VERSION 5.8 ;
BUSBITCHARS "[]" ;
DIVIDERCHAR "/" ;

SITE  CoreSite4
    CLASS       CORE ;
    SYMMETRY    Y ;
    SIZE        0.48 BY 15.12 ;
END  CoreSite4

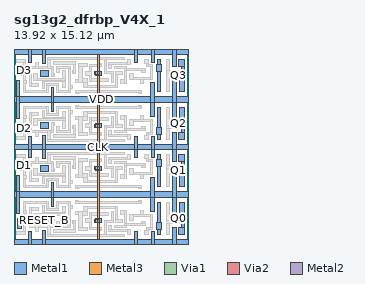
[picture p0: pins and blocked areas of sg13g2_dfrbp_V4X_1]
MACRO sg13g2_dfrbp_V4X_1
  CLASS CORE ;
  ORIGIN 0 0 ;
  FOREIGN sg13g2_dfrbp_V4X_1 0 0 ;
  SIZE 13.920 BY 15.120 ;
  SYMMETRY X Y ;
  SITE CoreSite4 ;
  PIN D0
    DIRECTION INPUT ;
    USE SIGNAL ;
    ANTENNAMODEL OXIDE1 ;
    ANTENNAGATEAREA 0.1092 LAYER Metal1 ;
    PORT
      LAYER Metal1 ;
        RECT 0.255 1.070 0.600 1.890 ;
    END
  END D0
  PIN Q0
    DIRECTION OUTPUT ;
    USE SIGNAL ;
    ANTENNADIFFAREA 0.6324 LAYER Metal1 ;
    PORT
      LAYER Metal1 ;
        RECT 13.125 0.590 13.560 1.190 ;
        RECT 13.350 0.590 13.560 3.155 ;
        RECT 13.145 2.095 13.560 3.155 ;
    END
  END Q0
  PIN Q_N0
    DIRECTION OUTPUT ;
    USE SIGNAL ;
    ANTENNADIFFAREA 0.7161 LAYER Metal1 ;
    PORT
      LAYER Metal1 ;
        RECT 11.340 0.990 11.725 1.520 ;
        RECT 11.400 0.590 11.660 3.155 ;
    END
  END Q_N0
  PIN D1
    DIRECTION INPUT ;
    USE SIGNAL ;
    ANTENNAMODEL OXIDE1 ;
    ANTENNAGATEAREA 0.1092 LAYER Metal1 ;
    PORT
      LAYER Metal1 ;
        RECT 0.255 5.670 0.600 6.490 ;
    END
  END D1
  PIN Q1
    DIRECTION OUTPUT ;
    USE SIGNAL ;
    ANTENNADIFFAREA 0.6324 LAYER Metal1 ;
    PORT
      LAYER Metal1 ;
        RECT 13.145 4.405 13.560 5.465 ;
        RECT 13.350 4.405 13.560 6.970 ;
        RECT 13.125 6.370 13.560 6.970 ;
    END
  END Q1
  PIN Q_N1
    DIRECTION OUTPUT ;
    USE SIGNAL ;
    ANTENNADIFFAREA 0.7161 LAYER Metal1 ;
    PORT
      LAYER Metal1 ;
        RECT 11.400 4.405 11.660 6.970 ;
        RECT 11.340 6.040 11.725 6.570 ;
    END
  END Q_N1
  PIN D2
    DIRECTION INPUT ;
    USE SIGNAL ;
    ANTENNAMODEL OXIDE1 ;
    ANTENNAGATEAREA 0.1092 LAYER Metal1 ;
    PORT
      LAYER Metal1 ;
        RECT 0.255 8.630 0.600 9.450 ;
    END
  END D2
  PIN Q2
    DIRECTION OUTPUT ;
    USE SIGNAL ;
    ANTENNADIFFAREA 0.6324 LAYER Metal1 ;
    PORT
      LAYER Metal1 ;
        RECT 13.125 8.150 13.560 8.750 ;
        RECT 13.350 8.150 13.560 10.715 ;
        RECT 13.145 9.655 13.560 10.715 ;
    END
  END Q2
  PIN Q_N2
    DIRECTION OUTPUT ;
    USE SIGNAL ;
    ANTENNADIFFAREA 0.7161 LAYER Metal1 ;
    PORT
      LAYER Metal1 ;
        RECT 11.340 8.550 11.725 9.080 ;
        RECT 11.400 8.150 11.660 10.715 ;
    END
  END Q_N2
  PIN D3
    DIRECTION INPUT ;
    USE SIGNAL ;
    ANTENNAMODEL OXIDE1 ;
    ANTENNAGATEAREA 0.1092 LAYER Metal1 ;
    PORT
      LAYER Metal1 ;
        RECT 0.255 13.230 0.600 14.050 ;
    END
  END D3
  PIN Q3
    DIRECTION OUTPUT ;
    USE SIGNAL ;
    ANTENNADIFFAREA 0.6324 LAYER Metal1 ;
    PORT
      LAYER Metal1 ;
        RECT 13.145 11.965 13.560 13.025 ;
        RECT 13.350 11.965 13.560 14.530 ;
        RECT 13.125 13.930 13.560 14.530 ;
    END
  END Q3
  PIN Q_N3
    DIRECTION OUTPUT ;
    USE SIGNAL ;
    ANTENNADIFFAREA 0.7161 LAYER Metal1 ;
    PORT
      LAYER Metal1 ;
        RECT 11.400 11.965 11.660 14.530 ;
        RECT 11.340 13.600 11.725 14.130 ;
    END
  END Q_N3
  PIN VDD
    DIRECTION INOUT ;
    USE POWER ;
    SHAPE ABUTMENT ;
    NETEXPR "VDD VDD!" ;
    PORT
      LAYER Metal1 ;
        RECT 12.630 2.100 12.900 4.000 ;
        RECT 0.215 2.240 0.475 4.000 ;
        RECT 10.890 2.460 11.150 4.000 ;
        RECT 2.945 2.860 3.115 4.000 ;
        RECT 0.000 3.560 13.920 4.000 ;
        RECT 2.945 3.560 3.115 4.700 ;
        RECT 10.890 3.560 11.150 5.100 ;
        RECT 0.215 3.560 0.475 5.320 ;
        RECT 12.630 3.560 12.900 5.460 ;
    END
    PORT
      LAYER Metal1 ;
        RECT 12.630 9.660 12.900 11.560 ;
        RECT 0.215 9.800 0.475 11.560 ;
        RECT 10.890 10.020 11.150 11.560 ;
        RECT 2.945 10.420 3.115 11.560 ;
        RECT 0.000 11.120 13.920 11.560 ;
        RECT 2.945 11.120 3.115 12.260 ;
        RECT 10.890 11.120 11.150 12.660 ;
        RECT 0.215 11.120 0.475 12.880 ;
        RECT 12.630 11.120 12.900 13.020 ;
    END
  END VDD
  PIN VSS
    DIRECTION INOUT ;
    USE GROUND ;
    SHAPE ABUTMENT ;
    NETEXPR "VSS VSS!" ;
    PORT
      LAYER Metal1 ;
        RECT 0.000 -0.220 13.920 0.220 ;
        RECT 10.910 -0.220 11.150 0.850 ;
        RECT 9.560 -0.220 9.820 0.850 ;
        RECT 1.140 -0.220 1.410 0.850 ;
        RECT 2.235 -0.220 2.495 0.915 ;
        RECT 12.635 -0.220 12.895 1.190 ;
    END
    PORT
      LAYER Metal1 ;
        RECT 12.635 6.370 12.895 7.780 ;
        RECT 2.235 6.645 2.495 7.780 ;
        RECT 10.910 6.710 11.150 7.780 ;
        RECT 9.560 6.710 9.820 7.780 ;
        RECT 1.140 6.710 1.410 7.780 ;
        RECT 0.000 7.340 13.920 7.780 ;
        RECT 10.910 7.340 11.150 8.410 ;
        RECT 9.560 7.340 9.820 8.410 ;
        RECT 1.140 7.340 1.410 8.410 ;
        RECT 2.235 7.340 2.495 8.475 ;
        RECT 12.635 7.340 12.895 8.750 ;
    END
    PORT
      LAYER Metal1 ;
        RECT 12.635 13.930 12.895 15.340 ;
        RECT 2.235 14.205 2.495 15.340 ;
        RECT 10.910 14.270 11.150 15.340 ;
        RECT 9.560 14.270 9.820 15.340 ;
        RECT 1.140 14.270 1.410 15.340 ;
        RECT 0.000 14.900 13.920 15.340 ;
    END
  END VSS
  PIN CLK
    DIRECTION INPUT ;
    USE SIGNAL ;
    ANTENNAMODEL OXIDE1 ;
    ANTENNAGATEAREA 0.2418 LAYER Metal1 ;
    PORT
      LAYER Metal1 ;
        RECT 6.450 1.520 6.990 1.840 ;
        RECT 6.450 5.720 6.990 6.040 ;
        RECT 6.450 9.080 6.990 9.400 ;
        RECT 6.450 13.280 6.990 13.600 ;
      LAYER Metal3 ;
        RECT 6.620 0.200 6.820 14.920 ;
      LAYER Via1 ;
        RECT 6.450 1.585 6.640 1.775 ;
      LAYER Via2 ;
        RECT 6.620 1.585 6.810 1.775 ;
      LAYER Metal2 ;
        RECT 6.445 1.580 6.815 1.780 ;
      LAYER Via1 ;
        RECT 6.450 5.785 6.640 5.975 ;
      LAYER Via2 ;
        RECT 6.620 5.785 6.810 5.975 ;
      LAYER Metal2 ;
        RECT 6.445 5.780 6.815 5.980 ;
      LAYER Via1 ;
        RECT 6.450 9.145 6.640 9.335 ;
      LAYER Via2 ;
        RECT 6.620 9.145 6.810 9.335 ;
      LAYER Metal2 ;
        RECT 6.445 9.140 6.815 9.340 ;
      LAYER Via1 ;
        RECT 6.450 13.345 6.640 13.535 ;
      LAYER Via2 ;
        RECT 6.620 13.345 6.810 13.535 ;
      LAYER Metal2 ;
        RECT 6.445 13.340 6.815 13.540 ;
    END
  END CLK
  PIN RESET_B
    DIRECTION INPUT ;
    USE SIGNAL ;
    ANTENNAPARTIALMETALAREA 0.8998 LAYER Metal1 ;
    ANTENNAMODEL OXIDE1 ;
    ANTENNAGATEAREA 0.3276 LAYER Metal1 ;
    ANTENNAMAXAREACAR 2.746642 LAYER Metal1 ;
    PORT
      LAYER Metal1 ;
        RECT 2.145 1.510 2.750 1.965 ;
    END
    PORT
      LAYER Metal1 ;
        RECT 2.145 5.595 2.750 6.050 ;
    END
    PORT
      LAYER Metal1 ;
        RECT 2.145 9.070 2.750 9.525 ;
    END
    PORT
      LAYER Metal1 ;
        RECT 2.145 13.155 2.750 13.610 ;
    END
  END RESET_B
  OBS
    LAYER Metal1 ;
      RECT 12.125 0.590 12.385 3.155 ;
      RECT 12.870 1.445 13.170 1.745 ;
      RECT 12.125 1.485 13.170 1.710 ;
      RECT 10.070 2.035 10.330 2.495 ;
      RECT 9.220 2.035 11.000 2.195 ;
      RECT 10.840 1.030 11.000 2.195 ;
      RECT 9.220 1.690 9.480 2.195 ;
      RECT 10.570 1.030 11.000 1.190 ;
      RECT 10.570 0.625 10.730 1.190 ;
      RECT 10.380 0.625 10.730 0.885 ;
      RECT 8.475 2.225 8.950 2.485 ;
      RECT 8.790 1.145 8.950 2.485 ;
      RECT 10.165 1.350 10.470 1.625 ;
      RECT 8.790 1.350 10.470 1.510 ;
      RECT 8.790 1.145 8.970 1.510 ;
      RECT 7.960 1.145 8.970 1.315 ;
      RECT 9.910 3.025 10.160 3.285 ;
      RECT 4.855 3.025 5.115 3.285 ;
      RECT 4.855 3.075 10.160 3.235 ;
      RECT 7.510 0.805 7.725 1.310 ;
      RECT 7.510 0.805 9.310 0.965 ;
      RECT 9.050 0.590 9.310 0.965 ;
      RECT 1.200 2.500 1.940 2.760 ;
      RECT 1.200 1.150 1.360 2.760 ;
      RECT 7.745 1.555 7.935 2.425 ;
      RECT 2.950 1.705 3.210 1.965 ;
      RECT 7.170 1.555 7.935 1.725 ;
      RECT 2.950 1.150 3.110 1.965 ;
      RECT 7.170 0.440 7.330 1.725 ;
      RECT 1.200 1.150 3.110 1.310 ;
      RECT 2.705 0.440 2.875 1.310 ;
      RECT 1.720 0.815 1.980 1.310 ;
      RECT 8.540 0.440 8.800 0.625 ;
      RECT 2.705 0.440 8.800 0.605 ;
      RECT 5.550 2.630 8.275 2.800 ;
      RECT 8.115 1.525 8.275 2.800 ;
      RECT 5.550 2.070 5.810 2.800 ;
      RECT 4.855 2.160 5.810 2.420 ;
      RECT 5.145 2.070 5.810 2.420 ;
      RECT 5.145 0.920 5.420 2.420 ;
      RECT 8.115 1.525 8.600 1.785 ;
      RECT 5.145 0.920 5.815 1.180 ;
      RECT 6.020 2.070 7.525 2.330 ;
      RECT 6.020 0.980 6.180 2.330 ;
      RECT 5.725 1.575 6.180 1.835 ;
      RECT 6.755 0.920 6.990 1.180 ;
      RECT 6.020 0.980 6.990 1.140 ;
      RECT 4.660 1.440 4.905 1.700 ;
      RECT 4.725 0.785 4.905 1.700 ;
      RECT 3.120 0.785 4.905 0.960 ;
      RECT 3.365 3.080 4.505 3.240 ;
      RECT 4.320 2.655 4.505 3.240 ;
      RECT 0.785 3.080 2.765 3.240 ;
      RECT 2.605 2.520 2.765 3.240 ;
      RECT 3.365 2.520 3.535 3.240 ;
      RECT 0.785 0.590 0.950 3.240 ;
      RECT 4.320 2.655 4.665 2.915 ;
      RECT 2.605 2.520 3.535 2.680 ;
      RECT 4.320 1.160 4.480 3.240 ;
      RECT 0.720 2.240 0.980 2.500 ;
      RECT 3.385 1.160 3.645 1.640 ;
      RECT 3.385 1.160 4.480 1.320 ;
      RECT 0.210 0.590 0.950 0.850 ;
      RECT 2.245 2.145 2.425 2.900 ;
      RECT 3.895 1.500 4.115 2.805 ;
      RECT 2.245 2.145 4.115 2.315 ;
      RECT 1.585 2.145 4.115 2.305 ;
      RECT 1.585 1.705 1.845 2.305 ;
      RECT 12.125 4.405 12.385 6.970 ;
      RECT 12.870 5.815 13.170 6.115 ;
      RECT 12.125 5.850 13.170 6.075 ;
      RECT 10.070 5.065 10.330 5.525 ;
      RECT 9.220 5.365 11.000 5.525 ;
      RECT 10.840 5.365 11.000 6.530 ;
      RECT 9.220 5.365 9.480 5.870 ;
      RECT 10.570 6.370 11.000 6.530 ;
      RECT 10.570 6.370 10.730 6.935 ;
      RECT 10.380 6.675 10.730 6.935 ;
      RECT 8.475 5.075 8.950 5.335 ;
      RECT 8.790 5.075 8.950 6.415 ;
      RECT 10.165 5.935 10.470 6.210 ;
      RECT 8.790 6.050 10.470 6.210 ;
      RECT 8.790 6.050 8.970 6.415 ;
      RECT 7.960 6.245 8.970 6.415 ;
      RECT 9.910 4.275 10.160 4.535 ;
      RECT 4.855 4.275 5.115 4.535 ;
      RECT 4.855 4.325 10.160 4.485 ;
      RECT 7.510 6.250 7.725 6.755 ;
      RECT 7.510 6.595 9.310 6.755 ;
      RECT 9.050 6.595 9.310 6.970 ;
      RECT 1.200 4.800 1.940 5.060 ;
      RECT 1.200 4.800 1.360 6.410 ;
      RECT 7.745 5.135 7.935 6.005 ;
      RECT 2.950 5.595 3.210 5.855 ;
      RECT 7.170 5.835 7.935 6.005 ;
      RECT 2.950 5.595 3.110 6.410 ;
      RECT 7.170 5.835 7.330 7.120 ;
      RECT 1.200 6.250 3.110 6.410 ;
      RECT 2.705 6.250 2.875 7.120 ;
      RECT 1.720 6.250 1.980 6.745 ;
      RECT 8.540 6.935 8.800 7.120 ;
      RECT 2.705 6.955 8.800 7.120 ;
      RECT 5.550 4.760 8.275 4.930 ;
      RECT 8.115 4.760 8.275 6.035 ;
      RECT 5.550 4.760 5.810 5.490 ;
      RECT 4.855 5.140 5.810 5.400 ;
      RECT 5.145 5.140 5.810 5.490 ;
      RECT 5.145 5.140 5.420 6.640 ;
      RECT 8.115 5.775 8.600 6.035 ;
      RECT 5.145 6.380 5.815 6.640 ;
      RECT 6.020 5.230 7.525 5.490 ;
      RECT 6.020 5.230 6.180 6.580 ;
      RECT 5.725 5.725 6.180 5.985 ;
      RECT 6.755 6.380 6.990 6.640 ;
      RECT 6.020 6.420 6.990 6.580 ;
      RECT 4.660 5.860 4.905 6.120 ;
      RECT 4.725 5.860 4.905 6.775 ;
      RECT 3.120 6.600 4.905 6.775 ;
      RECT 3.365 4.320 4.505 4.480 ;
      RECT 4.320 4.320 4.505 4.905 ;
      RECT 0.785 4.320 2.765 4.480 ;
      RECT 2.605 4.320 2.765 5.040 ;
      RECT 3.365 4.320 3.535 5.040 ;
      RECT 0.785 4.320 0.950 6.970 ;
      RECT 4.320 4.645 4.665 4.905 ;
      RECT 2.605 4.880 3.535 5.040 ;
      RECT 4.320 4.320 4.480 6.400 ;
      RECT 0.720 5.060 0.980 5.320 ;
      RECT 3.385 5.920 3.645 6.400 ;
      RECT 3.385 6.240 4.480 6.400 ;
      RECT 0.210 6.710 0.950 6.970 ;
      RECT 2.245 4.660 2.425 5.415 ;
      RECT 3.895 4.755 4.115 6.060 ;
      RECT 2.245 5.245 4.115 5.415 ;
      RECT 1.585 5.255 4.115 5.415 ;
      RECT 1.585 5.255 1.845 5.855 ;
      RECT 12.125 8.150 12.385 10.715 ;
      RECT 12.870 9.005 13.170 9.305 ;
      RECT 12.125 9.045 13.170 9.270 ;
      RECT 10.070 9.595 10.330 10.055 ;
      RECT 9.220 9.595 11.000 9.755 ;
      RECT 10.840 8.590 11.000 9.755 ;
      RECT 9.220 9.250 9.480 9.755 ;
      RECT 10.570 8.590 11.000 8.750 ;
      RECT 10.570 8.185 10.730 8.750 ;
      RECT 10.380 8.185 10.730 8.445 ;
      RECT 8.475 9.785 8.950 10.045 ;
      RECT 8.790 8.705 8.950 10.045 ;
      RECT 10.165 8.910 10.470 9.185 ;
      RECT 8.790 8.910 10.470 9.070 ;
      RECT 8.790 8.705 8.970 9.070 ;
      RECT 7.960 8.705 8.970 8.875 ;
      RECT 9.910 10.585 10.160 10.845 ;
      RECT 4.855 10.585 5.115 10.845 ;
      RECT 4.855 10.635 10.160 10.795 ;
      RECT 7.510 8.365 7.725 8.870 ;
      RECT 7.510 8.365 9.310 8.525 ;
      RECT 9.050 8.150 9.310 8.525 ;
      RECT 1.200 10.060 1.940 10.320 ;
      RECT 1.200 8.710 1.360 10.320 ;
      RECT 7.745 9.115 7.935 9.985 ;
      RECT 2.950 9.265 3.210 9.525 ;
      RECT 7.170 9.115 7.935 9.285 ;
      RECT 2.950 8.710 3.110 9.525 ;
      RECT 7.170 8.000 7.330 9.285 ;
      RECT 1.200 8.710 3.110 8.870 ;
      RECT 2.705 8.000 2.875 8.870 ;
      RECT 1.720 8.375 1.980 8.870 ;
      RECT 8.540 8.000 8.800 8.185 ;
      RECT 2.705 8.000 8.800 8.165 ;
      RECT 5.550 10.190 8.275 10.360 ;
      RECT 8.115 9.085 8.275 10.360 ;
      RECT 5.550 9.630 5.810 10.360 ;
      RECT 4.855 9.720 5.810 9.980 ;
      RECT 5.145 9.630 5.810 9.980 ;
      RECT 5.145 8.480 5.420 9.980 ;
      RECT 8.115 9.085 8.600 9.345 ;
      RECT 5.145 8.480 5.815 8.740 ;
      RECT 6.020 9.630 7.525 9.890 ;
      RECT 6.020 8.540 6.180 9.890 ;
      RECT 5.725 9.135 6.180 9.395 ;
      RECT 6.755 8.480 6.990 8.740 ;
      RECT 6.020 8.540 6.990 8.700 ;
      RECT 4.660 9.000 4.905 9.260 ;
      RECT 4.725 8.345 4.905 9.260 ;
      RECT 3.120 8.345 4.905 8.520 ;
      RECT 3.365 10.640 4.505 10.800 ;
      RECT 4.320 10.215 4.505 10.800 ;
      RECT 0.785 10.640 2.765 10.800 ;
      RECT 2.605 10.080 2.765 10.800 ;
      RECT 3.365 10.080 3.535 10.800 ;
      RECT 0.785 8.150 0.950 10.800 ;
      RECT 4.320 10.215 4.665 10.475 ;
      RECT 2.605 10.080 3.535 10.240 ;
      RECT 4.320 8.720 4.480 10.800 ;
      RECT 0.720 9.800 0.980 10.060 ;
      RECT 3.385 8.720 3.645 9.200 ;
      RECT 3.385 8.720 4.480 8.880 ;
      RECT 0.210 8.150 0.950 8.410 ;
      RECT 2.245 9.705 2.425 10.460 ;
      RECT 3.895 9.060 4.115 10.365 ;
      RECT 2.245 9.705 4.115 9.875 ;
      RECT 1.585 9.705 4.115 9.865 ;
      RECT 1.585 9.265 1.845 9.865 ;
      RECT 12.125 11.965 12.385 14.530 ;
      RECT 12.870 13.375 13.170 13.675 ;
      RECT 12.125 13.410 13.170 13.635 ;
      RECT 10.070 12.625 10.330 13.085 ;
      RECT 9.220 12.925 11.000 13.085 ;
      RECT 10.840 12.925 11.000 14.090 ;
      RECT 9.220 12.925 9.480 13.430 ;
      RECT 10.570 13.930 11.000 14.090 ;
      RECT 10.570 13.930 10.730 14.495 ;
      RECT 10.380 14.235 10.730 14.495 ;
      RECT 8.475 12.635 8.950 12.895 ;
      RECT 8.790 12.635 8.950 13.975 ;
      RECT 10.165 13.495 10.470 13.770 ;
      RECT 8.790 13.610 10.470 13.770 ;
      RECT 8.790 13.610 8.970 13.975 ;
      RECT 7.960 13.805 8.970 13.975 ;
      RECT 9.910 11.835 10.160 12.095 ;
      RECT 4.855 11.835 5.115 12.095 ;
      RECT 4.855 11.885 10.160 12.045 ;
      RECT 7.510 13.810 7.725 14.315 ;
      RECT 7.510 14.155 9.310 14.315 ;
      RECT 9.050 14.155 9.310 14.530 ;
      RECT 1.200 12.360 1.940 12.620 ;
      RECT 1.200 12.360 1.360 13.970 ;
      RECT 7.745 12.695 7.935 13.565 ;
      RECT 2.950 13.155 3.210 13.415 ;
      RECT 7.170 13.395 7.935 13.565 ;
      RECT 2.950 13.155 3.110 13.970 ;
      RECT 7.170 13.395 7.330 14.680 ;
      RECT 1.200 13.810 3.110 13.970 ;
      RECT 2.705 13.810 2.875 14.680 ;
      RECT 1.720 13.810 1.980 14.305 ;
      RECT 8.540 14.495 8.800 14.680 ;
      RECT 2.705 14.515 8.800 14.680 ;
      RECT 5.550 12.320 8.275 12.490 ;
      RECT 8.115 12.320 8.275 13.595 ;
      RECT 5.550 12.320 5.810 13.050 ;
      RECT 4.855 12.700 5.810 12.960 ;
      RECT 5.145 12.700 5.810 13.050 ;
      RECT 5.145 12.700 5.420 14.200 ;
      RECT 8.115 13.335 8.600 13.595 ;
      RECT 5.145 13.940 5.815 14.200 ;
      RECT 6.020 12.790 7.525 13.050 ;
      RECT 6.020 12.790 6.180 14.140 ;
      RECT 5.725 13.285 6.180 13.545 ;
      RECT 6.755 13.940 6.990 14.200 ;
      RECT 6.020 13.980 6.990 14.140 ;
      RECT 4.660 13.420 4.905 13.680 ;
      RECT 4.725 13.420 4.905 14.335 ;
      RECT 3.120 14.160 4.905 14.335 ;
      RECT 3.365 11.880 4.505 12.040 ;
      RECT 4.320 11.880 4.505 12.465 ;
      RECT 0.785 11.880 2.765 12.040 ;
      RECT 2.605 11.880 2.765 12.600 ;
      RECT 3.365 11.880 3.535 12.600 ;
      RECT 0.785 11.880 0.950 14.530 ;
      RECT 4.320 12.205 4.665 12.465 ;
      RECT 2.605 12.440 3.535 12.600 ;
      RECT 4.320 11.880 4.480 13.960 ;
      RECT 0.720 12.620 0.980 12.880 ;
      RECT 3.385 13.480 3.645 13.960 ;
      RECT 3.385 13.800 4.480 13.960 ;
      RECT 0.210 14.270 0.950 14.530 ;
      RECT 2.245 12.220 2.425 12.975 ;
      RECT 3.895 12.315 4.115 13.620 ;
      RECT 2.245 12.805 4.115 12.975 ;
      RECT 1.585 12.815 4.115 12.975 ;
      RECT 1.585 12.815 1.845 13.415 ;
  END
END sg13g2_dfrbp_V4X_1

END LIBRARY
